VERSION 5.8 ;
BUSBITCHARS "[]" ;
UNITS DISTANCE MICRONS 1000 ;

SITE CORE_SITE
  CLASS CORE ;
  SIZE 0.60 BY 1.20 ;
END CORE_SITE

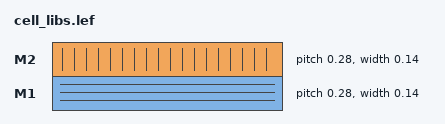
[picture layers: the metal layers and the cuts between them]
LAYER M1
  TYPE ROUTING ;
  DIRECTION HORIZONTAL ;
  PITCH 0.28 ;
  WIDTH 0.14 ;
END M1

LAYER M2
  TYPE ROUTING ;
  DIRECTION VERTICAL ;
  PITCH 0.28 ;
  WIDTH 0.14 ;
END M2

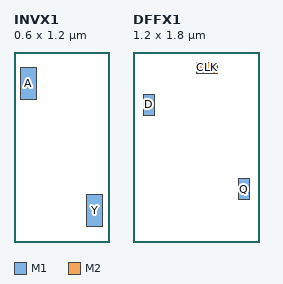
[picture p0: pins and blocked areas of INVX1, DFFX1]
MACRO INVX1
  CLASS CORE ;
  ORIGIN 0 0 ;
  SIZE 0.60 BY 1.20 ;
  SITE CORE_SITE ;
  PIN A
    DIRECTION INPUT ;
    PORT
      LAYER M1 ;
        RECT 0.04 0.90 0.14 1.10 ;
    END
  END A
  PIN Y
    DIRECTION OUTPUT ;
    PORT
      LAYER M1 ;
        RECT 0.46 0.10 0.56 0.30 ;
    END
  END Y
END INVX1

MACRO DFFX1
  CLASS CORE ;
  ORIGIN 0 0 ;
  SIZE 1.20 BY 1.80 ;
  SITE CORE_SITE ;
  PIN D
    DIRECTION INPUT ;
    PORT
      LAYER M1 ;
        RECT 0.10 1.20 0.20 1.40 ;
    END
  END D
  PIN Q
    DIRECTION OUTPUT ;
    PORT
      LAYER M1 ;
        RECT 1.00 0.40 1.10 0.60 ;
    END
  END Q
  PIN CLK
    DIRECTION INPUT ;
    PORT
      LAYER M2 ;
        RECT 0.60 1.60 0.80 1.70 ;
    END
  END CLK
END DFFX1

END LIBRARY
